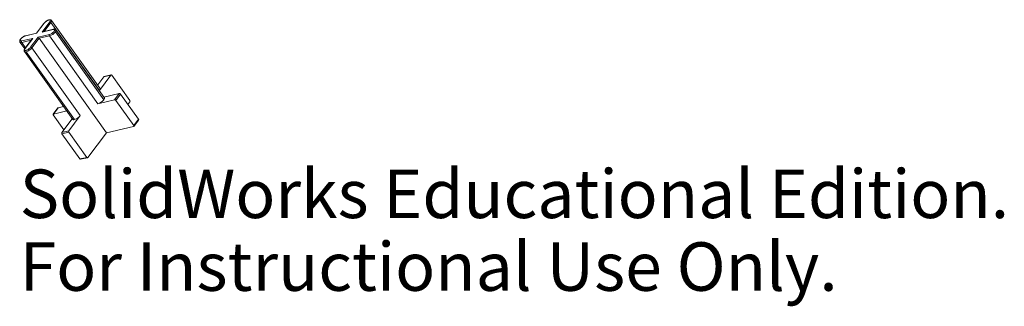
# Model space of a CAD drawing. Units: millimetres. Extents: x -3.4 to 94.7, y -24.7 to 3.8.
import ezdxf

# ---------------------------------------------------------------- set-up
doc = ezdxf.new("R2010")
doc.units = ezdxf.units.MM
doc.styles.add('SLDTEXTSTYLE0', font='TXT', dxfattribs={"width": 0.7})

msp = doc.modelspace()

# ---------------------------------------------------------------- linework, layer by layer
at = {"color": 7, "linetype": 'Continuous', "lineweight": 15}
for p, q in [((-0.976, 3.459), (-1.716, 2.479)), ((-0.95, 3.475), (-1.712, 2.466)), ((-1.158, 2.595), (-0.396, 3.603)), ((-0.273, 3.544), (-0.94, 2.66)), ((4.549, -3.216), (-0.273, 3.544)), ((4.61, -3.006), (-0.212, 3.754)), ((-1.712, 2.466), (-2.82, 2.209)), ((-1.716, 2.48), (-2.789, 2.23)), ((-2.3, 1.082), (-1.539, 2.091)), ((-1.463, 1.968), (-2.177, 1.022)), ((-1.539, 2.091), (-0.43, 2.348)), ((-0.424, 2.209), (-1.463, 1.968)), ((-1.463, 1.968), (5.255, -7.45)), ((-0.049, 2.852), (-1.158, 2.595)), ((-0.018, 2.874), (-1.091, 2.625)), ((4.398, -4.551), (-0.424, 2.209)), ((0.161, 2.605), (4.982, -4.155)), ((5.043, -3.945), (0.221, 2.815)), ((-3.364, 1.591), (-2.889, 0.925)), ((-3.201, 1.705), (-2.093, 1.962)), ((-2.238, 1.788), (-3.195, 1.566)), ((-3.195, 1.566), (-2.811, 1.029)), ((-2.14, 1.918), (-2.88, 0.938)), ((-2.093, 1.962), (-2.854, 0.954)), ((-2.177, 1.022), (2.645, -5.737)), ((-2.93, 0.652), (1.891, -6.108)), ((-2.761, 0.627), (2.06, -6.133)), ((4.999, -1.864), (4.38, -2.684)), ((5.692, -1.703), (4.549, -3.216)), ((5.692, -1.703), (4.999, -1.864)), ((5.723, -1.682), (5.03, -1.843)), ((5.793, -1.716), (7.581, -4.223)), ((6.537, -3.534), (5.004, -3.89)), ((6.06, -4.165), (6.537, -3.534)), ((6.66, -3.594), (6.184, -4.225)), ((8.448, -6.101), (6.66, -3.594)), ((0.441, -4.949), (0.976, -4.825)), ((6.06, -4.165), (4.398, -4.551)), ((6.184, -4.225), (7.972, -6.731)), ((7.588, -4.362), (7.392, -4.621)), ((0.415, -4.965), (-0.061, -5.595)), ((1.005, -7.152), (-0.051, -5.672)), ((0.441, -4.949), (-0.035, -5.58)), ((-0.035, -5.58), (1.294, -5.271)), ((1.502, -7.25), (2.645, -5.737)), ((0.809, -7.411), (1.844, -6.041)), ((7.957, -6.823), (5.255, -7.45)), ((7.972, -6.731), (8.448, -6.101)), ((7.982, -6.807), (8.458, -6.177)), ((0.809, -7.411), (1.502, -7.25)), ((1.509, -7.389), (0.816, -7.55)), ((0.816, -7.55), (2.604, -10.056)), ((3.296, -9.895), (1.509, -7.389)), ((5.255, -7.45), (3.398, -9.908)), ((2.604, -10.056), (3.296, -9.895)), ((2.674, -10.091), (3.367, -9.93))]:
    msp.add_line(p, q, dxfattribs=at)
at = {"color": 7, "linetype": 'Continuous', "lineweight": 15, "flags": 128}
for points in [[(-0.95, 3.475), (-0.91, 3.522), (-0.863, 3.57), (-0.808, 3.617), (-0.75, 3.661), (-0.688, 3.702), (-0.626, 3.736), (-0.566, 3.764), (-0.509, 3.784), (-0.458, 3.796), (-0.414, 3.799), (-0.379, 3.794), (-0.354, 3.779), (-0.34, 3.757), (-0.337, 3.727), (-0.346, 3.69), (-0.366, 3.649), (-0.396, 3.603)], [(-0.212, 3.753), (-0.206, 3.743), (-0.199, 3.713), (-0.202, 3.678), (-0.216, 3.637), (-0.24, 3.592), (-0.273, 3.544)], [(-3.201, 1.705), (-3.249, 1.697), (-3.288, 1.699), (-3.318, 1.709), (-3.338, 1.727), (-3.347, 1.754), (-3.344, 1.787), (-3.329, 1.826), (-3.304, 1.87), (-3.269, 1.916), (-3.225, 1.964), (-3.174, 2.012), (-3.117, 2.058), (-3.057, 2.1), (-2.995, 2.137), (-2.933, 2.169), (-2.874, 2.193), (-2.82, 2.209)], [(-0.049, 2.852), (-0.002, 2.86), (0.038, 2.858), (0.068, 2.848), (0.088, 2.83), (0.096, 2.803), (0.093, 2.77), (0.079, 2.731), (0.054, 2.687), (0.019, 2.641), (-0.025, 2.593), (-0.077, 2.545), (-0.133, 2.5), (-0.194, 2.457), (-0.256, 2.42), (-0.317, 2.388), (-0.376, 2.364), (-0.43, 2.348)], [(0.161, 2.605), (0.194, 2.653), (0.217, 2.698), (0.231, 2.739), (0.234, 2.774), (0.228, 2.804), (0.221, 2.815)], [(-2.3, 1.082), (-2.34, 1.035), (-2.388, 0.987), (-2.442, 0.94), (-2.501, 0.896), (-2.562, 0.855), (-2.624, 0.821), (-2.685, 0.793), (-2.741, 0.773), (-2.793, 0.761), (-2.836, 0.758), (-2.871, 0.764), (-2.896, 0.778), (-2.91, 0.801), (-2.913, 0.83), (-2.905, 0.867), (-2.885, 0.908), (-2.854, 0.954)], [(-2.761, 0.627), (-2.813, 0.618), (-2.857, 0.617), (-2.893, 0.625), (-2.919, 0.64), (-2.93, 0.652)], [(5.793, -1.716), (5.782, -1.703), (5.769, -1.692), (5.755, -1.685), (5.741, -1.681), (5.727, -1.681), (5.714, -1.685), (5.702, -1.692), (5.692, -1.703)], [(4.61, -3.006), (4.616, -3.017), (4.623, -3.046), (4.619, -3.082), (4.606, -3.123), (4.582, -3.168), (4.549, -3.216)], [(5.043, -3.945), (5.049, -3.956), (5.056, -3.985), (5.053, -4.021), (5.039, -4.062), (5.015, -4.107), (4.982, -4.155)], [(-0.035, -5.58), (-0.048, -5.584), (-0.058, -5.592), (-0.065, -5.601), (-0.069, -5.613), (-0.069, -5.627), (-0.066, -5.641), (-0.06, -5.657), (-0.051, -5.672)], [(2.06, -6.133), (2.009, -6.142), (1.965, -6.142), (1.929, -6.135), (1.902, -6.12), (1.891, -6.108)], [(7.957, -6.823), (7.969, -6.818), (7.979, -6.811), (7.986, -6.801), (7.99, -6.789), (7.99, -6.776), (7.987, -6.761), (7.981, -6.746), (7.972, -6.731)], [(3.296, -9.895), (3.308, -9.909), (3.321, -9.92), (3.335, -9.927), (3.349, -9.931), (3.363, -9.931), (3.376, -9.927), (3.388, -9.919), (3.398, -9.908)]]:
    msp.add_lwpolyline(points, dxfattribs=at)
at = {"color": 7, "linetype": 'Continuous', "lineweight": 15}
for centre, radius, start, end in [((-0.942, 3.433), 0.0429, 100.97878, 141.95509), ((-0.384, 3.47), 0.134, 33.30633, 94.94793), ((-2.775, 2.177), 0.0552, 103.97533, 144.44672), ((-1.694, 2.479), 0.0216, 178.36378, 215.06641), ((-0.691, 2.529), 0.955, 207.3401, 216.01553), ((-1.045, 2.431), 0.199, 103.39443, 124.50811), ((-0.324, 2.283), 0.125, 148.73745, 216.67378), ((-0.752, 3.324), 1.162, 286.42188, 321.76341), ((-0.004, 2.82), 0.0552, 104.00637, 144.44591), ((-3.259, 1.716), 0.163, 230.28141, 293.23818), ((-3.095, 1.64), 0.125, 148.73745, 216.67378), ((-3.09, 1.742), 1.162, 286.42188, 321.76341), ((-2.289, 0.949), 0.134, 33.30633, 94.94793), ((-1.982, 1.797), 0.199, 123.79455, 142.57158), ((-2.846, 0.911), 0.0429, 100.98029, 141.91221), ((5.044, -1.896), 0.0552, 103.97533, 144.44672), ((6.548, -3.668), 0.134, 33.30633, 94.94793), ((4.069, -3.436), 1.162, 286.42188, 321.76341), ((6.072, -4.298), 0.134, 33.30633, 94.94793), ((7.481, -4.297), 0.125, 328.73745, 36.67378), ((0.449, -4.992), 0.0429, 100.97878, 141.95509), ((1.732, -5.018), 1.162, 286.42188, 321.76341), ((8.4, -6.146), 0.0657, 331.92551, 43.77155), ((0.916, -7.475), 0.125, 148.73745, 216.67378), ((1.609, -7.315), 0.125, 148.73745, 216.67378), ((2.664, -10.022), 0.0694, 209.65694, 278.17095)]:
    msp.add_arc(centre, radius, start, end, dxfattribs=at)
for points, knots in [([(-0.212, 3.753), (-0.212, 3.754), (-0.219, 3.766), (-0.241, 3.785), (-0.274, 3.807), (-0.312, 3.819), (-0.354, 3.824), (-0.403, 3.822), (-0.457, 3.812), (-0.517, 3.794), (-0.579, 3.769), (-0.642, 3.737), (-0.703, 3.701), (-0.763, 3.661), (-0.821, 3.617), (-0.874, 3.571), (-0.923, 3.523), (-0.956, 3.485), (-0.972, 3.464), (-0.976, 3.459)], [0, 0, 0, 0, 0.003363, 0.055364, 0.105892, 0.157767, 0.214286, 0.278414, 0.350148, 0.423679, 0.495309, 0.565323, 0.634355, 0.702892, 0.771309, 0.839886, 0.908933, 0.978908, 1, 1, 1, 1]), ([(-2.789, 2.23), (-2.799, 2.228), (-2.828, 2.221), (-2.88, 2.202), (-2.942, 2.175), (-3.004, 2.141), (-3.065, 2.103), (-3.124, 2.062), (-3.18, 2.017), (-3.232, 1.97), (-3.278, 1.921), (-3.319, 1.872), (-3.352, 1.821), (-3.377, 1.771), (-3.39, 1.724), (-3.394, 1.681), (-3.389, 1.641), (-3.378, 1.61), (-3.366, 1.595), (-3.362, 1.591)], [0, 0, 0, 0, 0.035238, 0.103932, 0.170895, 0.23658, 0.301535, 0.366172, 0.430823, 0.495712, 0.561202, 0.627783, 0.696194, 0.767482, 0.828912, 0.882403, 0.931403, 0.978367, 1, 1, 1, 1]), ([(0.22, 2.815), (0.215, 2.821), (0.203, 2.839), (0.174, 2.859), (0.139, 2.875), (0.098, 2.884), (0.053, 2.885), (0.014, 2.881), (-0.011, 2.875), (-0.018, 2.874)], [0, 0, 0, 0, 0.089775, 0.239684, 0.389203, 0.548087, 0.725848, 0.92791, 1, 1, 1, 1]), ([(-2.88, 0.938), (-2.886, 0.929), (-2.905, 0.903), (-2.931, 0.86), (-2.951, 0.81), (-2.96, 0.764), (-2.959, 0.722), (-2.95, 0.684), (-2.937, 0.662), (-2.93, 0.652)], [0, 0, 0, 0, 0.093002, 0.278442, 0.471561, 0.623021, 0.758048, 0.884727, 1, 1, 1, 1])]:
    msp.add_open_spline(points, degree=3, knots=knots, dxfattribs=at)

# ---------------------------------------------------------------- texts
at = {"color": 7, "linetype": 'Continuous', "char_height": 4.83362, "attachment_point": 1, "style": 'SLDTEXTSTYLE0'}
for s, insert in [('SolidWorks Educational Edition.', (-3.393, -11.111)), ('For Instructional Use Only.', (-3.393, -18.361))]:
    msp.add_mtext(s, dxfattribs=dict(at, insert=insert))

doc.saveas('drawing.dxf')
